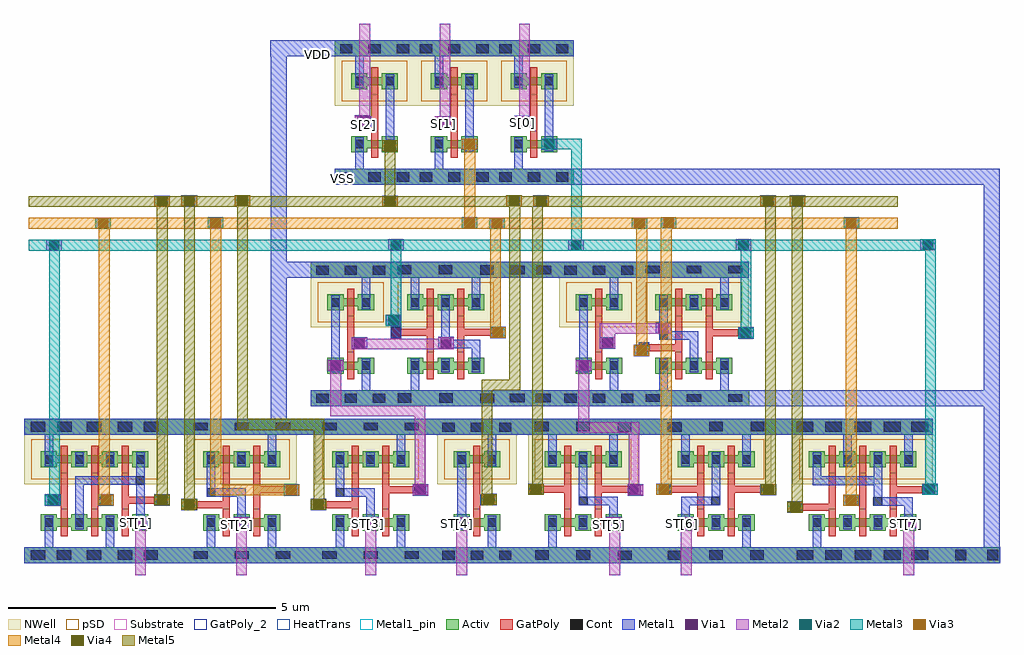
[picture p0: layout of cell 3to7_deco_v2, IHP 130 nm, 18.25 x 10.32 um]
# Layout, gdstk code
from math import pi, radians
import gdstk
lib = gdstk.Library(unit=1e-6, precision=5e-09)
def R(c, l, rs):  # rectangles x0, y0, x1, y1
    for r in rs: c.add(gdstk.rectangle(r[:2], r[2:], *l))
def A(c, l, x, y, w, h, nx, ny, dx, dy):  # array of equal rectangles
    R(c, l, [(x+i*dx, y+j*dy, x+i*dx+w, y+j*dy+h) for i in range(nx) for j in range(ny)])
Activ = (1, 0)
GatPoly = (5, 0)
GatPoly_2 = (5, 2)
Cont = (6, 0)
Metal1 = (8, 0)
Metal1_pin = (8, 2)
Metal2 = (10, 0)
pSD = (14, 0)
Via1 = (19, 0)
Via2 = (29, 0)
Metal3 = (30, 0)
NWell = (31, 0)
Substrate = (40, 0)
Via3 = (49, 0)
Metal4 = (50, 0)
HeatTrans = (51, 0)
Via4 = (66, 0)
Metal5 = (67, 0)

pmos_1 = lib.new_cell('pmos$1')
R(pmos_1, Activ, [(0,0,0.3,0.3), (0.57,0,0.87,0.3), (0,0.075,0.87,0.225)])
R(pmos_1, GatPoly, [(0.37,-0.105,0.5,0.405), (0.37,-0.105,0.5,0.405)])
R(pmos_1, Cont, [(0.07,0.07,0.23,0.23), (0.64,0.07,0.8,0.23)])
R(pmos_1, Metal1, [(0.07,0.02,0.23,0.28), (0.07,0.02,0.23,0.28), (0.64,0.02,0.8,0.28), (0.64,0.02,0.8,0.28)])
R(pmos_1, pSD, [(-0.18,-0.225,1.05,0.525)])
R(pmos_1, NWell, [(-0.31,-0.31,1.18,0.61)])
R(pmos_1, Substrate, [(0.57,0,0.87,0.3)])
R(pmos_1, HeatTrans, [(0.37,-0.105,0.5,0.405)])
pmos_1.add(gdstk.Label('pmos', (0.435,0.15), layer=63, texttype=0))
pmos_1.add(gdstk.Label('pmos', (0.435,0.15), layer=51, texttype=0))

nmos_1 = lib.new_cell('nmos$1')
R(nmos_1, Activ, [(0,0,0.3,0.3), (0.57,0,0.87,0.3), (0,0.075,0.87,0.225)])
R(nmos_1, GatPoly, [(0.37,-0.105,0.5,0.405)])
R(nmos_1, GatPoly_2, [(0.37,-0.105,0.5,0.405)])
R(nmos_1, Cont, [(0.07,0.07,0.23,0.23), (0.64,0.07,0.8,0.23)])
R(nmos_1, Metal1, [(0.07,0.02,0.23,0.28), (0.64,0.02,0.8,0.28)])
R(nmos_1, Metal1_pin, [(0.07,0.02,0.23,0.28), (0.64,0.02,0.8,0.28)])
R(nmos_1, HeatTrans, [(0.37,-0.105,0.5,0.405)])
nmos_1.add(gdstk.Label('nmos', (0.435,0.15), layer=63, texttype=0))
nmos_1.add(gdstk.Label('nmos', (0.435,0.15), layer=51, texttype=0))

pmos_1_1 = lib.new_cell('pmos$1$1')
R(pmos_1_1, Activ, [(0,0,0.3,0.3), (0.57,0,0.87,0.3), (0,0.075,0.87,0.225)])
R(pmos_1_1, GatPoly, [(0.37,-0.105,0.5,0.405), (0.37,-0.105,0.5,0.405)])
R(pmos_1_1, Cont, [(0.07,0.07,0.23,0.23), (0.64,0.07,0.8,0.23)])
R(pmos_1_1, Metal1, [(0.07,0.02,0.23,0.28), (0.07,0.02,0.23,0.28), (0.64,0.02,0.8,0.28), (0.64,0.02,0.8,0.28)])
R(pmos_1_1, pSD, [(-0.18,-0.225,1.05,0.525)])
R(pmos_1_1, NWell, [(-0.31,-0.31,1.18,0.61)])
R(pmos_1_1, Substrate, [(0.57,0,0.87,0.3)])
R(pmos_1_1, HeatTrans, [(0.37,-0.105,0.5,0.405)])
pmos_1_1.add(gdstk.Label('pmos', (0.435,0.15), layer=63, texttype=0))
pmos_1_1.add(gdstk.Label('pmos', (0.435,0.15), layer=51, texttype=0))

nmos_1_1 = lib.new_cell('nmos$1$1')
R(nmos_1_1, Activ, [(0,0,0.3,0.3), (0.57,0,0.87,0.3), (0,0.075,0.87,0.225)])
R(nmos_1_1, GatPoly, [(0.37,-0.105,0.5,0.405)])
R(nmos_1_1, GatPoly_2, [(0.37,-0.105,0.5,0.405)])
R(nmos_1_1, Cont, [(0.07,0.07,0.23,0.23), (0.64,0.07,0.8,0.23)])
R(nmos_1_1, Metal1, [(0.07,0.02,0.23,0.28), (0.64,0.02,0.8,0.28)])
R(nmos_1_1, Metal1_pin, [(0.07,0.02,0.23,0.28), (0.64,0.02,0.8,0.28)])
R(nmos_1_1, HeatTrans, [(0.37,-0.105,0.5,0.405)])
nmos_1_1.add(gdstk.Label('nmos', (0.435,0.15), layer=63, texttype=0))
nmos_1_1.add(gdstk.Label('nmos', (0.435,0.15), layer=51, texttype=0))

pmos_1_2 = lib.new_cell('pmos$1$2')
R(pmos_1_2, Activ, [(0,0,0.3,0.3), (0.57,0,0.87,0.3), (0,0.075,0.87,0.225)])
R(pmos_1_2, GatPoly, [(0.37,-0.105,0.5,0.405), (0.37,-0.105,0.5,0.405)])
R(pmos_1_2, Cont, [(0.07,0.07,0.23,0.23), (0.64,0.07,0.8,0.23)])
R(pmos_1_2, Metal1, [(0.07,0.02,0.23,0.28), (0.07,0.02,0.23,0.28), (0.64,0.02,0.8,0.28), (0.64,0.02,0.8,0.28)])
R(pmos_1_2, pSD, [(-0.18,-0.225,1.05,0.525)])
R(pmos_1_2, NWell, [(-0.31,-0.31,1.18,0.61)])
R(pmos_1_2, Substrate, [(0.57,0,0.87,0.3)])
R(pmos_1_2, HeatTrans, [(0.37,-0.105,0.5,0.405)])
pmos_1_2.add(gdstk.Label('pmos', (0.435,0.15), layer=63, texttype=0))
pmos_1_2.add(gdstk.Label('pmos', (0.435,0.15), layer=51, texttype=0))

nmos_1_2 = lib.new_cell('nmos$1$2')
R(nmos_1_2, Activ, [(0,0,0.3,0.3), (0.57,0,0.87,0.3), (0,0.075,0.87,0.225)])
R(nmos_1_2, GatPoly, [(0.37,-0.105,0.5,0.405)])
R(nmos_1_2, GatPoly_2, [(0.37,-0.105,0.5,0.405)])
R(nmos_1_2, Cont, [(0.07,0.07,0.23,0.23), (0.64,0.07,0.8,0.23)])
R(nmos_1_2, Metal1, [(0.07,0.02,0.23,0.28), (0.64,0.02,0.8,0.28)])
R(nmos_1_2, Metal1_pin, [(0.07,0.02,0.23,0.28), (0.64,0.02,0.8,0.28)])
R(nmos_1_2, HeatTrans, [(0.37,-0.105,0.5,0.405)])
nmos_1_2.add(gdstk.Label('nmos', (0.435,0.15), layer=63, texttype=0))
nmos_1_2.add(gdstk.Label('nmos', (0.435,0.15), layer=51, texttype=0))

inv = lib.new_cell('inv')
R(inv, Activ, [(0.24,0.255,1.73,0.555), (0.24,0.255,1.73,0.555), (0.24,0.255,1.73,0.555), (0.24,0.255,1.73,0.555), (0.24,2.655,1.73,2.955), (0.24,2.655,1.73,2.955), (0.24,2.655,1.73,2.955), (0.24,2.655,1.73,2.955)])
R(inv, GatPoly, [(0.92,0.76,1.05,2.45), (0.92,0.76,1.05,2.45), (0.92,0.76,1.05,2.45), (0.92,0.76,1.05,2.45), (0.72,1.335,0.92,1.535), (0.72,1.335,0.92,1.535), (0.72,1.335,0.92,1.535), (0.72,1.335,0.92,1.535)])
R(inv, Cont, [(0.34,0.315,0.57,0.485), (0.34,0.315,0.57,0.485), (0.34,0.315,0.57,0.485), (0.34,0.315,0.57,0.485), (0.87,0.315,1.1,0.485), (0.87,0.315,1.1,0.485), (0.87,0.315,1.1,0.485), (0.87,0.315,1.1,0.485), (1.4,0.315,1.63,0.485), (1.4,0.315,1.63,0.485), (1.4,0.315,1.63,0.485), (1.4,0.315,1.63,0.485), (0.72,1.335,0.92,1.535), (0.72,1.335,0.92,1.535), (0.72,1.335,0.92,1.535), (0.72,1.335,0.92,1.535), (0.34,2.715,0.57,2.885), (0.34,2.715,0.57,2.885), (0.34,2.715,0.57,2.885), (0.34,2.715,0.57,2.885), (0.87,2.715,1.1,2.885), (0.87,2.715,1.1,2.885), (0.87,2.715,1.1,2.885), (0.87,2.715,1.1,2.885), (1.4,2.715,1.63,2.885), (1.4,2.715,1.63,2.885), (1.4,2.715,1.63,2.885), (1.4,2.715,1.63,2.885)])
R(inv, Metal1, [(0.24,0.255,1.73,0.555), (0.24,0.255,1.73,0.555), (0.24,0.255,1.73,0.555), (0.24,0.255,1.73,0.555), (0.62,0.255,0.78,1.145), (0.62,0.255,0.78,1.145), (0.62,0.255,0.78,1.145), (0.62,0.255,0.78,1.145), (1.19,0.885,1.35,2.325), (1.19,0.885,1.35,2.325), (1.19,0.885,1.35,2.325), (1.19,0.885,1.35,2.325), (0.72,1.335,0.92,1.535), (0.72,1.335,0.92,1.535), (0.72,1.335,0.92,1.535), (0.72,1.335,0.92,1.535), (0.62,2.065,0.78,2.955), (0.62,2.065,0.78,2.955), (0.62,2.065,0.78,2.955), (0.62,2.065,0.78,2.955), (0.24,2.655,1.73,2.955), (0.24,2.655,1.73,2.955), (0.24,2.655,1.73,2.955), (0.24,2.655,1.73,2.955)])
R(inv, Metal1_pin, [(0.24,0.255,1.73,0.555), (0.24,0.255,1.73,0.555), (0.24,0.255,1.73,0.555), (0.24,0.255,1.73,0.555), (1.19,0.885,1.35,2.325), (1.19,0.885,1.35,2.325), (1.19,0.885,1.35,2.325), (1.19,0.885,1.35,2.325), (0.72,1.335,0.92,1.535), (0.72,1.335,0.92,1.535), (0.72,1.335,0.92,1.535), (0.72,1.335,0.92,1.535), (0.24,2.655,1.73,2.955), (0.24,2.655,1.73,2.955), (0.24,2.655,1.73,2.955), (0.24,2.655,1.73,2.955)])
R(inv, pSD, [(0.24,0.255,1.73,0.555), (0.24,0.255,1.73,0.555), (0.24,0.255,1.73,0.555), (0.24,0.255,1.73,0.555)])
R(inv, NWell, [(0.24,2.655,1.73,2.955), (0.24,2.655,1.73,2.955), (0.24,2.655,1.73,2.955), (0.24,2.655,1.73,2.955)])
inv.add(gdstk.Reference(pmos_1, (0.55,2.045)))
inv.add(gdstk.Reference(nmos_1, (0.55,0.865)))
inv.add(gdstk.Reference(pmos_1_1, (0.55,2.045)))
inv.add(gdstk.Reference(nmos_1_1, (0.55,0.865)))
inv.add(gdstk.Reference(pmos_1_2, (0.55,2.045)))
inv.add(gdstk.Reference(nmos_1_2, (0.55,0.865)))
inv.add(gdstk.Label('VIN', (0.78,1.435), layer=8, texttype=25))
inv.add(gdstk.Label('VSS', (0.95,0.37), layer=8, texttype=25))
inv.add(gdstk.Label('VOUT', (1.2,1.665), layer=8, texttype=25))
inv.add(gdstk.Label('VDD', (0.96,2.805), layer=8, texttype=25))
inv.add(gdstk.Label('VIN', (0.78,1.435), layer=8, texttype=25))
inv.add(gdstk.Label('VSS', (0.95,0.37), layer=8, texttype=25))
inv.add(gdstk.Label('VOUT', (1.2,1.665), layer=8, texttype=25))
inv.add(gdstk.Label('VDD', (0.96,2.805), layer=8, texttype=25))
inv.add(gdstk.Label('VIN', (0.78,1.435), layer=8, texttype=25))
inv.add(gdstk.Label('VSS', (0.95,0.37), layer=8, texttype=25))
inv.add(gdstk.Label('VOUT', (1.2,1.665), layer=8, texttype=25))
inv.add(gdstk.Label('VDD', (0.96,2.805), layer=8, texttype=25))
inv.add(gdstk.Label('VIN', (0.78,1.435), layer=8, texttype=25))
inv.add(gdstk.Label('VSS', (0.95,0.37), layer=8, texttype=25))
inv.add(gdstk.Label('VOUT', (1.2,1.665), layer=8, texttype=25))
inv.add(gdstk.Label('VDD', (0.96,2.805), layer=8, texttype=25))

nmos_3 = lib.new_cell('nmos$3')
R(nmos_3, Activ, [(0,0,0.3,0.3), (0.57,0,0.87,0.3), (0,0.075,0.87,0.225)])
R(nmos_3, GatPoly, [(0.37,-0.105,0.5,0.405)])
R(nmos_3, GatPoly_2, [(0.37,-0.105,0.5,0.405)])
R(nmos_3, Cont, [(0.07,0.07,0.23,0.23), (0.64,0.07,0.8,0.23)])
R(nmos_3, Metal1, [(0.07,0.02,0.23,0.28), (0.64,0.02,0.8,0.28)])
R(nmos_3, Metal1_pin, [(0.07,0.02,0.23,0.28), (0.64,0.02,0.8,0.28)])
R(nmos_3, HeatTrans, [(0.37,-0.105,0.5,0.405)])
nmos_3.add(gdstk.Label('nmos', (0.435,0.15), layer=63, texttype=0))
nmos_3.add(gdstk.Label('nmos', (0.435,0.15), layer=51, texttype=0))

pmos_3 = lib.new_cell('pmos$3')
R(pmos_3, Activ, [(0,0,0.3,0.3), (0.57,0,0.87,0.3), (0,0.075,0.87,0.225)])
R(pmos_3, GatPoly, [(0.37,-0.105,0.5,0.405), (0.37,-0.105,0.5,0.405)])
R(pmos_3, Cont, [(0.07,0.07,0.23,0.23), (0.64,0.07,0.8,0.23)])
R(pmos_3, Metal1, [(0.07,0.02,0.23,0.28), (0.07,0.02,0.23,0.28), (0.64,0.02,0.8,0.28), (0.64,0.02,0.8,0.28)])
R(pmos_3, pSD, [(-0.18,-0.225,1.05,0.525)])
R(pmos_3, NWell, [(-0.31,-0.31,1.18,0.61)])
R(pmos_3, Substrate, [(0.57,0,0.87,0.3)])
R(pmos_3, HeatTrans, [(0.37,-0.105,0.5,0.405)])
pmos_3.add(gdstk.Label('pmos', (0.435,0.15), layer=63, texttype=0))
pmos_3.add(gdstk.Label('pmos', (0.435,0.15), layer=51, texttype=0))

nmos_2_1 = lib.new_cell('nmos$2$1')
R(nmos_2_1, Activ, [(0,0,0.3,0.3), (0.57,0,0.87,0.3), (0,0.075,0.87,0.225)])
R(nmos_2_1, GatPoly, [(0.37,-0.105,0.5,0.405)])
R(nmos_2_1, GatPoly_2, [(0.37,-0.105,0.5,0.405)])
R(nmos_2_1, Cont, [(0.07,0.07,0.23,0.23), (0.64,0.07,0.8,0.23)])
R(nmos_2_1, Metal1, [(0.07,0.02,0.23,0.28), (0.64,0.02,0.8,0.28)])
R(nmos_2_1, Metal1_pin, [(0.07,0.02,0.23,0.28), (0.64,0.02,0.8,0.28)])
R(nmos_2_1, HeatTrans, [(0.37,-0.105,0.5,0.405)])
nmos_2_1.add(gdstk.Label('nmos', (0.435,0.15), layer=63, texttype=0))
nmos_2_1.add(gdstk.Label('nmos', (0.435,0.15), layer=51, texttype=0))

pmos_2_1 = lib.new_cell('pmos$2$1')
R(pmos_2_1, Activ, [(0,0,0.3,0.3), (0.57,0,0.87,0.3), (0,0.075,0.87,0.225)])
R(pmos_2_1, GatPoly, [(0.37,-0.105,0.5,0.405), (0.37,-0.105,0.5,0.405)])
R(pmos_2_1, Cont, [(0.07,0.07,0.23,0.23), (0.64,0.07,0.8,0.23)])
R(pmos_2_1, Metal1, [(0.07,0.02,0.23,0.28), (0.07,0.02,0.23,0.28), (0.64,0.02,0.8,0.28), (0.64,0.02,0.8,0.28)])
R(pmos_2_1, pSD, [(-0.18,-0.225,1.05,0.525)])
R(pmos_2_1, NWell, [(-0.31,-0.31,1.18,0.61)])
R(pmos_2_1, Substrate, [(0.57,0,0.87,0.3)])
R(pmos_2_1, HeatTrans, [(0.37,-0.105,0.5,0.405)])
pmos_2_1.add(gdstk.Label('pmos', (0.435,0.15), layer=63, texttype=0))
pmos_2_1.add(gdstk.Label('pmos', (0.435,0.15), layer=51, texttype=0))

nand_custom = lib.new_cell('nand_custom')
R(nand_custom, Activ, [(0.95,1.7,3.01,2), (0.95,1.7,3.01,2), (0.95,1.7,3.01,2), (0.95,4.1,3.01,4.4), (0.95,4.1,3.01,4.4), (0.95,4.1,3.01,4.4)])
R(nand_custom, GatPoly, [(1.63,2.205,1.76,3.895), (1.63,2.205,1.76,3.895), (1.63,2.205,1.76,3.895), (2.2,2.205,2.33,3.895), (2.2,2.205,2.33,3.895), (2.2,2.205,2.33,3.895), (0.95,2.975,1.15,3.175), (0.95,2.975,1.15,3.175), (0.95,2.975,1.15,3.175), (2.81,2.975,3.01,3.175), (2.81,2.975,3.01,3.175), (2.81,2.975,3.01,3.175), (1.15,3.02,1.76,3.15), (1.15,3.02,1.76,3.15), (1.15,3.02,1.76,3.15), (2.2,3.02,2.81,3.15), (2.2,3.02,2.81,3.15), (2.2,3.02,2.81,3.15)])
R(nand_custom, Cont, [(1.075,1.76,1.33,1.935), (1.075,1.76,1.33,1.935), (1.075,1.76,1.33,1.935), (1.85,1.765,2.105,1.94), (1.85,1.765,2.105,1.94), (1.85,1.765,2.105,1.94), (2.62,1.765,2.875,1.94), (2.62,1.765,2.875,1.94), (2.62,1.765,2.875,1.94), (1.895,2.785,2.06,2.945), (1.895,2.785,2.06,2.945), (1.895,2.785,2.06,2.945), (0.95,2.975,1.15,3.175), (0.95,2.975,1.15,3.175), (0.95,2.975,1.15,3.175), (2.81,2.975,3.01,3.175), (2.81,2.975,3.01,3.175), (2.81,2.975,3.01,3.175), (1.08,4.16,1.335,4.335), (1.08,4.16,1.335,4.335), (1.08,4.16,1.335,4.335), (1.855,4.165,2.11,4.34), (1.855,4.165,2.11,4.34), (1.855,4.165,2.11,4.34), (2.625,4.165,2.88,4.34), (2.625,4.165,2.88,4.34), (2.625,4.165,2.88,4.34)])
R(nand_custom, Metal1, [(0.95,1.7,3.01,2), (0.95,1.7,3.01,2), (0.95,1.7,3.01,2), (2.47,1.7,2.63,2.59), (2.47,1.7,2.63,2.59), (2.47,1.7,2.63,2.59), (1.33,2.33,1.49,2.945), (1.33,2.33,1.49,2.945), (1.33,2.33,1.49,2.945), (1.33,2.785,2.06,2.945), (1.33,2.785,2.06,2.945), (1.33,2.785,2.06,2.945), (1.9,2.785,2.06,3.77), (1.9,2.785,2.06,3.77), (1.9,2.785,2.06,3.77), (0.95,2.975,1.15,3.175), (0.95,2.975,1.15,3.175), (0.95,2.975,1.15,3.175), (2.81,2.975,3.01,3.175), (2.81,2.975,3.01,3.175), (2.81,2.975,3.01,3.175), (1.33,3.51,1.49,4.4), (1.33,3.51,1.49,4.4), (1.33,3.51,1.49,4.4), (2.47,3.51,2.63,4.4), (2.47,3.51,2.63,4.4), (2.47,3.51,2.63,4.4), (0.95,4.1,3.01,4.4), (0.95,4.1,3.01,4.4), (0.95,4.1,3.01,4.4)])
R(nand_custom, Metal1_pin, [(0.95,1.7,3.01,2), (0.95,1.7,3.01,2), (0.95,1.7,3.01,2), (1.9,2.785,2.06,3.77), (1.9,2.785,2.06,3.77), (1.9,2.785,2.06,3.77), (0.95,2.975,1.15,3.175), (0.95,2.975,1.15,3.175), (0.95,2.975,1.15,3.175), (2.81,2.975,3.01,3.175), (2.81,2.975,3.01,3.175), (2.81,2.975,3.01,3.175), (0.95,4.1,3.01,4.4), (0.95,4.1,3.01,4.4), (0.95,4.1,3.01,4.4)])
R(nand_custom, pSD, [(0.95,1.7,3.01,2), (0.95,1.7,3.01,2), (0.95,1.7,3.01,2)])
R(nand_custom, NWell, [(0.95,4.1,3.01,4.4), (0.95,4.1,3.01,4.4), (0.95,4.1,3.01,4.4)])
nand_custom.add(gdstk.Reference(nmos_3, (1.26,2.31)))
nand_custom.add(gdstk.Reference(nmos_3, (1.83,2.31)))
nand_custom.add(gdstk.Reference(pmos_3, (2.7,3.79), rotation=pi))
nand_custom.add(gdstk.Reference(pmos_3, (1.26,3.49)))
nand_custom.add(gdstk.Reference(nmos_2_1, (1.26,2.31)))
nand_custom.add(gdstk.Reference(nmos_2_1, (1.83,2.31)))
nand_custom.add(gdstk.Reference(pmos_2_1, (2.7,3.79), rotation=pi))
nand_custom.add(gdstk.Reference(pmos_2_1, (1.26,3.49)))
nand_custom.add(gdstk.Label('VSS', (1.94,1.84), layer=8, texttype=25))
nand_custom.add(gdstk.Label('A', (1.05,3.075), layer=8, texttype=25))
nand_custom.add(gdstk.Label('OUT', (1.925,2.83), layer=8, texttype=25))
nand_custom.add(gdstk.Label('B', (2.89,3.08), layer=8, texttype=25))
nand_custom.add(gdstk.Label('VDD', (1.93,4.21), layer=8, texttype=25))
nand_custom.add(gdstk.Label('VSS', (1.94,1.84), layer=8, texttype=25))
nand_custom.add(gdstk.Label('A', (1.05,3.075), layer=8, texttype=25))
nand_custom.add(gdstk.Label('OUT', (1.925,2.83), layer=8, texttype=25))
nand_custom.add(gdstk.Label('B', (2.89,3.08), layer=8, texttype=25))
nand_custom.add(gdstk.Label('VDD', (1.93,4.21), layer=8, texttype=25))
nand_custom.add(gdstk.Label('VSS', (1.94,1.84), layer=8, texttype=25))
nand_custom.add(gdstk.Label('A', (1.05,3.075), layer=8, texttype=25))
nand_custom.add(gdstk.Label('OUT', (1.925,2.83), layer=8, texttype=25))
nand_custom.add(gdstk.Label('B', (2.89,3.08), layer=8, texttype=25))
nand_custom.add(gdstk.Label('VDD', (1.93,4.21), layer=8, texttype=25))

via_stack_1 = lib.new_cell('via_stack$1')
R(via_stack_1, Metal1, [(-0.145,-0.105,0.145,0.105)])
R(via_stack_1, Metal2, [(-0.145,-0.1,0.145,0.1)])
R(via_stack_1, Via1, [(-0.095,-0.095,0.095,0.095)])

and_custom = lib.new_cell('and_custom')
R(and_custom, Metal2, [(2.61,1.32,4.515,1.52)])
and_custom.add(gdstk.Reference(inv, (3.55,0)))
and_custom.add(gdstk.Reference(nand_custom, (0.78,-1.445)))
and_custom.add(gdstk.Reference(via_stack_1, (4.37,1.435)))
and_custom.add(gdstk.Reference(via_stack_1, (2.755,1.445)))
and_custom.add(gdstk.Label('A', (1.775,1.61), layer=8, texttype=25))
and_custom.add(gdstk.Label('B', (3.69,1.63), layer=8, texttype=25))
and_custom.add(gdstk.Label('VSS', (1.925,0.385), layer=8, texttype=25))
and_custom.add(gdstk.Label('VDD', (1.93,2.765), layer=8, texttype=25))
and_custom.add(gdstk.Label('OUT', (4.775,1.6), layer=8, texttype=25))

via_stack = lib.new_cell('via_stack')
R(via_stack, Metal1, [(-0.145,-0.105,0.145,0.105)])
R(via_stack, Metal2, [(-0.145,-0.1,0.145,0.1)])
R(via_stack, Via1, [(-0.095,-0.095,0.095,0.095)])

pmos_2 = lib.new_cell('pmos$2')
R(pmos_2, Activ, [(0,0,0.3,0.3), (0.57,0,0.87,0.3), (0,0.075,0.87,0.225)])
R(pmos_2, GatPoly, [(0.37,-0.105,0.5,0.405), (0.37,-0.105,0.5,0.405)])
R(pmos_2, Cont, [(0.07,0.07,0.23,0.23), (0.64,0.07,0.8,0.23)])
R(pmos_2, Metal1, [(0.07,0.02,0.23,0.28), (0.07,0.02,0.23,0.28), (0.64,0.02,0.8,0.28), (0.64,0.02,0.8,0.28)])
R(pmos_2, pSD, [(-0.18,-0.225,1.05,0.525)])
R(pmos_2, NWell, [(-0.31,-0.31,1.18,0.61)])
R(pmos_2, Substrate, [(0.57,0,0.87,0.3)])
R(pmos_2, HeatTrans, [(0.37,-0.105,0.5,0.405)])
pmos_2.add(gdstk.Label('pmos', (0.435,0.15), layer=63, texttype=0))
pmos_2.add(gdstk.Label('pmos', (0.435,0.15), layer=51, texttype=0))

nmos_2 = lib.new_cell('nmos$2')
R(nmos_2, Activ, [(0,0,0.3,0.3), (0.57,0,0.87,0.3), (0,0.075,0.87,0.225)])
R(nmos_2, GatPoly, [(0.37,-0.105,0.5,0.405)])
R(nmos_2, GatPoly_2, [(0.37,-0.105,0.5,0.405)])
R(nmos_2, Cont, [(0.07,0.07,0.23,0.23), (0.64,0.07,0.8,0.23)])
R(nmos_2, Metal1, [(0.07,0.02,0.23,0.28), (0.64,0.02,0.8,0.28)])
R(nmos_2, Metal1_pin, [(0.07,0.02,0.23,0.28), (0.64,0.02,0.8,0.28)])
R(nmos_2, HeatTrans, [(0.37,-0.105,0.5,0.405)])
nmos_2.add(gdstk.Label('nmos', (0.435,0.15), layer=63, texttype=0))
nmos_2.add(gdstk.Label('nmos', (0.435,0.15), layer=51, texttype=0))

pmos_4 = lib.new_cell('pmos$4')
R(pmos_4, Activ, [(0,0,0.3,0.3), (0.57,0,0.87,0.3), (0,0.075,0.87,0.225)])
R(pmos_4, GatPoly, [(0.37,-0.105,0.5,0.405), (0.37,-0.105,0.5,0.405)])
R(pmos_4, Cont, [(0.07,0.07,0.23,0.23), (0.64,0.07,0.8,0.23)])
R(pmos_4, Metal1, [(0.07,0.02,0.23,0.28), (0.07,0.02,0.23,0.28), (0.64,0.02,0.8,0.28), (0.64,0.02,0.8,0.28)])
R(pmos_4, pSD, [(-0.18,-0.225,1.05,0.525)])
R(pmos_4, NWell, [(-0.31,-0.31,1.18,0.61)])
R(pmos_4, Substrate, [(0.57,0,0.87,0.3)])
R(pmos_4, HeatTrans, [(0.37,-0.105,0.5,0.405)])
pmos_4.add(gdstk.Label('pmos', (0.435,0.15), layer=63, texttype=0))
pmos_4.add(gdstk.Label('pmos', (0.435,0.15), layer=51, texttype=0))

nmos_4 = lib.new_cell('nmos$4')
R(nmos_4, Activ, [(0,0,0.3,0.3), (0.57,0,0.87,0.3), (0,0.075,0.87,0.225)])
R(nmos_4, GatPoly, [(0.37,-0.105,0.5,0.405)])
R(nmos_4, GatPoly_2, [(0.37,-0.105,0.5,0.405)])
R(nmos_4, Cont, [(0.07,0.07,0.23,0.23), (0.64,0.07,0.8,0.23)])
R(nmos_4, Metal1, [(0.07,0.02,0.23,0.28), (0.64,0.02,0.8,0.28)])
R(nmos_4, Metal1_pin, [(0.07,0.02,0.23,0.28), (0.64,0.02,0.8,0.28)])
R(nmos_4, HeatTrans, [(0.37,-0.105,0.5,0.405)])
nmos_4.add(gdstk.Label('nmos', (0.435,0.15), layer=63, texttype=0))
nmos_4.add(gdstk.Label('nmos', (0.435,0.15), layer=51, texttype=0))

nor_custom = lib.new_cell('nor_custom')
R(nor_custom, Activ, [(0.165,0.28,2.225,0.58), (0.165,0.28,2.225,0.58), (0.17,2.68,2.23,2.98), (0.17,2.68,2.23,2.98)])
R(nor_custom, GatPoly, [(0.85,0.785,0.98,2.475), (0.85,0.785,0.98,2.475), (1.42,0.785,1.55,2.475), (1.42,0.785,1.55,2.475), (1.42,1.31,2.03,1.44), (1.42,1.31,2.03,1.44), (0.37,1.585,0.98,1.715), (0.37,1.585,0.98,1.715)])
R(nor_custom, Cont, [(0.295,0.36,0.56,0.505), (0.295,0.36,0.56,0.505), (1.065,0.36,1.33,0.505), (1.065,0.36,1.33,0.505), (1.835,0.36,2.1,0.505), (1.835,0.36,2.1,0.505), (2.03,1.275,2.23,1.475), (2.03,1.275,2.23,1.475), (1.69,1.52,1.85,1.68), (1.69,1.52,1.85,1.68), (0.17,1.55,0.37,1.75), (0.17,1.55,0.37,1.75), (0.295,2.765,0.56,2.91), (0.295,2.765,0.56,2.91), (1.065,2.765,1.33,2.91), (1.065,2.765,1.33,2.91), (1.835,2.765,2.1,2.91), (1.835,2.765,2.1,2.91)])
R(nor_custom, Metal1, [(0.165,0.28,2.225,0.58), (0.165,0.28,2.225,0.58), (0.55,0.28,0.71,1.17), (0.55,0.28,0.71,1.17), (1.69,0.28,1.85,1.17), (1.69,0.28,1.85,1.17), (1.12,0.91,1.28,1.68), (1.12,0.91,1.28,1.68), (2.03,1.275,2.23,1.475), (2.03,1.275,2.23,1.475), (1.12,1.52,1.85,1.68), (1.12,1.52,1.85,1.68), (1.69,1.52,1.85,2.35), (1.69,1.52,1.85,2.35), (0.17,1.55,0.37,1.75), (0.17,1.55,0.37,1.75), (0.55,2.09,0.71,2.98), (0.55,2.09,0.71,2.98), (0.17,2.68,2.23,2.98), (0.17,2.68,2.23,2.98)])
R(nor_custom, Metal1_pin, [(0.165,0.28,2.225,0.58), (0.165,0.28,2.225,0.58), (2.03,1.275,2.23,1.475), (2.03,1.275,2.23,1.475), (1.69,1.52,1.85,2.35), (1.69,1.52,1.85,2.35), (0.17,1.55,0.37,1.75), (0.17,1.55,0.37,1.75), (0.17,2.68,2.23,2.98), (0.17,2.68,2.23,2.98)])
R(nor_custom, pSD, [(0.165,0.28,2.225,0.58), (0.165,0.28,2.225,0.58)])
R(nor_custom, NWell, [(0.17,2.68,2.23,2.98), (0.17,2.68,2.23,2.98)])
nor_custom.add(gdstk.Reference(pmos_2, (0.48,2.07)))
nor_custom.add(gdstk.Reference(pmos_2, (1.05,2.07)))
nor_custom.add(gdstk.Reference(nmos_2, (1.92,1.19), rotation=pi))
nor_custom.add(gdstk.Reference(nmos_2, (0.48,0.89)))
nor_custom.add(gdstk.Reference(pmos_4, (0.48,2.07)))
nor_custom.add(gdstk.Reference(pmos_4, (1.05,2.07)))
nor_custom.add(gdstk.Reference(nmos_4, (1.92,1.19), rotation=pi))
nor_custom.add(gdstk.Reference(nmos_4, (0.48,0.89)))
nor_custom.add(gdstk.Label('VSS', (1.155,0.405), layer=8, texttype=25))
nor_custom.add(gdstk.Label('A', (0.23,1.6), layer=8, texttype=25))
nor_custom.add(gdstk.Label('B', (2.085,1.35), layer=8, texttype=25))
nor_custom.add(gdstk.Label('OUT', (1.735,1.555), layer=8, texttype=25))
nor_custom.add(gdstk.Label('VDD', (1.13,2.815), layer=8, texttype=25))
nor_custom.add(gdstk.Label('VSS', (1.155,0.405), layer=8, texttype=25))
nor_custom.add(gdstk.Label('A', (0.23,1.6), layer=8, texttype=25))
nor_custom.add(gdstk.Label('B', (2.085,1.35), layer=8, texttype=25))
nor_custom.add(gdstk.Label('OUT', (1.735,1.555), layer=8, texttype=25))
nor_custom.add(gdstk.Label('VDD', (1.13,2.815), layer=8, texttype=25))

or_custom = lib.new_cell('or_custom')
R(or_custom, Activ, [(0.165,0.28,3.72,0.58)])
R(or_custom, Metal1, [(0.165,0.28,3.72,0.58), (0.165,0.28,3.72,0.58)])
R(or_custom, Metal1_pin, [(0.165,0.28,3.72,0.58)])
R(or_custom, Metal2, [(2.665,1.36,2.955,1.835), (1.625,1.635,2.955,1.835)])
or_custom.add(gdstk.Reference(inv, (1.99,0.025)))
or_custom.add(gdstk.Reference(via_stack, (2.81,1.46)))
or_custom.add(gdstk.Reference(via_stack, (1.77,1.735)))
or_custom.add(gdstk.Reference(nor_custom, (0,0)))
or_custom.add(gdstk.Label('OUT', (3.23,1.65), layer=8, texttype=25))
or_custom.add(gdstk.Label('A', (0.27,1.65), layer=8, texttype=25))
or_custom.add(gdstk.Label('B', (2.105,1.335), layer=8, texttype=25))
or_custom.add(gdstk.Label('VSS', (1.915,0.395), layer=8, texttype=25))
or_custom.add(gdstk.Label('VDD', (1.885,2.82), layer=8, texttype=25))

via_stack_3 = lib.new_cell('via_stack$3')
R(via_stack_3, Metal1, [(-0.145,-0.105,0.145,0.105)])
R(via_stack_3, Metal2, [(-0.145,-0.1,0.145,0.1)])
R(via_stack_3, Via1, [(-0.095,-0.095,0.095,0.095)])
R(via_stack_3, Via2, [(-0.095,-0.095,0.095,0.095)])
R(via_stack_3, Metal3, [(-0.145,-0.1,0.145,0.1)])
R(via_stack_3, Via3, [(-0.095,-0.095,0.095,0.095)])
R(via_stack_3, Metal4, [(-0.145,-0.1,0.145,0.1)])
R(via_stack_3, Via4, [(-0.095,-0.095,0.095,0.095)])
R(via_stack_3, Metal5, [(-0.145,-0.1,0.145,0.1)])

via_stack_4 = lib.new_cell('via_stack$4')
R(via_stack_4, Metal1, [(-0.145,-0.105,0.145,0.105)])
R(via_stack_4, Metal2, [(-0.145,-0.1,0.145,0.1)])
R(via_stack_4, Via1, [(-0.095,-0.095,0.095,0.095)])
R(via_stack_4, Via2, [(-0.095,-0.095,0.095,0.095)])
R(via_stack_4, Metal3, [(-0.145,-0.1,0.145,0.1)])
R(via_stack_4, Via3, [(-0.095,-0.095,0.095,0.095)])
R(via_stack_4, Metal4, [(-0.145,-0.1,0.145,0.1)])

via_stack_6 = lib.new_cell('via_stack$6')
R(via_stack_6, Metal1, [(-0.145,-0.105,0.145,0.105)])
R(via_stack_6, Metal2, [(-0.145,-0.1,0.145,0.1)])
R(via_stack_6, Via1, [(-0.095,-0.095,0.095,0.095)])
R(via_stack_6, Via2, [(-0.095,-0.095,0.095,0.095)])
R(via_stack_6, Metal3, [(-0.145,-0.1,0.145,0.1)])

pmos_5 = lib.new_cell('pmos$5')
R(pmos_5, Activ, [(0,0,0.3,0.3), (0.57,0,0.87,0.3), (0,0.075,0.87,0.225)])
R(pmos_5, GatPoly, [(0.37,-0.105,0.5,0.405), (0.37,-0.105,0.5,0.405)])
R(pmos_5, Cont, [(0.07,0.07,0.23,0.23), (0.64,0.07,0.8,0.23)])
R(pmos_5, Metal1, [(0.07,0.02,0.23,0.28), (0.07,0.02,0.23,0.28), (0.64,0.02,0.8,0.28), (0.64,0.02,0.8,0.28)])
R(pmos_5, pSD, [(-0.18,-0.225,1.05,0.525)])
R(pmos_5, NWell, [(-0.31,-0.31,1.18,0.61)])
R(pmos_5, Substrate, [(0.57,0,0.87,0.3)])
R(pmos_5, HeatTrans, [(0.37,-0.105,0.5,0.405)])
pmos_5.add(gdstk.Label('pmos', (0.435,0.15), layer=63, texttype=0))
pmos_5.add(gdstk.Label('pmos', (0.435,0.15), layer=51, texttype=0))

nmos_5 = lib.new_cell('nmos$5')
R(nmos_5, Activ, [(0,0,0.3,0.3), (0.57,0,0.87,0.3), (0,0.075,0.87,0.225)])
R(nmos_5, GatPoly, [(0.37,-0.105,0.5,0.405)])
R(nmos_5, GatPoly_2, [(0.37,-0.105,0.5,0.405)])
R(nmos_5, Cont, [(0.07,0.07,0.23,0.23), (0.64,0.07,0.8,0.23)])
R(nmos_5, Metal1, [(0.07,0.02,0.23,0.28), (0.64,0.02,0.8,0.28)])
R(nmos_5, Metal1_pin, [(0.07,0.02,0.23,0.28), (0.64,0.02,0.8,0.28)])
R(nmos_5, HeatTrans, [(0.37,-0.105,0.5,0.405)])
nmos_5.add(gdstk.Label('nmos', (0.435,0.15), layer=63, texttype=0))
nmos_5.add(gdstk.Label('nmos', (0.435,0.15), layer=51, texttype=0))

nand_x3_custom = lib.new_cell('nand_x3_custom')
R(nand_x3_custom, Activ, [(0.82,3.075,3.45,3.375), (0.82,5.475,3.45,5.775)])
A(nand_x3_custom, GatPoly, 1.5, 3.58, 0.13, 1.69, 3, 1, 0.57, 0)
R(nand_x3_custom, GatPoly, [(2.64,4.055,3.25,4.185), (1.02,4.385,1.5,4.515)])
A(nand_x3_custom, Cont, 1.425, 3.135, 0.31, 0.185, 3, 2, 0.55, 2.395)
R(nand_x3_custom, Cont, [(0.91,3.135,1.22,3.32), (3.055,3.135,3.365,3.32), (3.25,4.02,3.45,4.22), (2.2,4.145,2.4,4.345), (1.77,4.15,1.935,4.31), (0.82,4.35,1.02,4.55), (0.91,5.53,1.22,5.715), (3.055,5.53,3.365,5.715)])
R(nand_x3_custom, Metal1, [(0.82,3.075,3.45,3.375), (2.91,3.075,3.07,3.965), (1.2,3.705,1.36,4.305), (3.25,4.02,3.45,4.22), (1.2,4.145,1.93,4.305), (1.77,4.145,1.93,5.145), (2.2,4.145,2.4,4.345), (0.82,4.35,1.02,4.55), (1.77,4.535,3.07,4.7), (2.91,4.535,3.07,5.145), (1.2,4.885,1.36,5.775), (2.34,4.885,2.5,5.775), (0.82,5.475,3.45,5.775)])
R(nand_x3_custom, Metal1_pin, [(0.82,3.075,3.45,3.375), (3.25,4.02,3.45,4.22), (1.77,4.145,1.93,5.145), (2.2,4.145,2.4,4.345), (0.82,4.35,1.02,4.55), (0.82,5.475,3.45,5.775)])
R(nand_x3_custom, pSD, [(0.82,3.075,3.45,3.375)])
R(nand_x3_custom, NWell, [(0.82,5.475,3.45,5.775)])
nand_x3_custom.add(gdstk.Reference(pmos_5, (2.57,5.165), rotation=pi))
nand_x3_custom.add(gdstk.Reference(pmos_5, (2.27,4.865)))
nand_x3_custom.add(gdstk.Reference(nmos_5, (2,3.985), rotation=pi))
nand_x3_custom.add(gdstk.Reference(nmos_5, (2.57,3.985), rotation=pi))
nand_x3_custom.add(gdstk.Reference(nmos_5, (3.14,3.985), rotation=pi))
nand_x3_custom.add(gdstk.Reference(pmos_5, (1.13,4.865)))
nand_x3_custom.add(gdstk.Label('C', (3.355,4.08), layer=8, texttype=25))
nand_x3_custom.add(gdstk.Label('VSS', (2.135,3.185), layer=8, texttype=25))
nand_x3_custom.add(gdstk.Label('A', (0.88,4.4), layer=8, texttype=25))
nand_x3_custom.add(gdstk.Label('B', (2.28,4.2), layer=8, texttype=25))
nand_x3_custom.add(gdstk.Label('OUT', (1.785,4.205), layer=8, texttype=25))
nand_x3_custom.add(gdstk.Label('VDD', (2.075,5.575), layer=8, texttype=25))

nmos = lib.new_cell('nmos')
R(nmos, Activ, [(0,0,0.3,0.3), (0.57,0,0.87,0.3), (0,0.075,0.87,0.225)])
R(nmos, GatPoly, [(0.37,-0.105,0.5,0.405)])
R(nmos, GatPoly_2, [(0.37,-0.105,0.5,0.405)])
R(nmos, Cont, [(0.07,0.07,0.23,0.23), (0.64,0.07,0.8,0.23)])
R(nmos, Metal1, [(0.07,0.02,0.23,0.28), (0.64,0.02,0.8,0.28)])
R(nmos, Metal1_pin, [(0.07,0.02,0.23,0.28), (0.64,0.02,0.8,0.28)])
R(nmos, HeatTrans, [(0.37,-0.105,0.5,0.405)])
nmos.add(gdstk.Label('nmos', (0.435,0.15), layer=63, texttype=0))
nmos.add(gdstk.Label('nmos', (0.435,0.15), layer=51, texttype=0))

pmos = lib.new_cell('pmos')
R(pmos, Activ, [(0,0,0.3,0.3), (0.57,0,0.87,0.3), (0,0.075,0.87,0.225)])
R(pmos, GatPoly, [(0.37,-0.105,0.5,0.405), (0.37,-0.105,0.5,0.405)])
R(pmos, Cont, [(0.07,0.07,0.23,0.23), (0.64,0.07,0.8,0.23)])
R(pmos, Metal1, [(0.07,0.02,0.23,0.28), (0.07,0.02,0.23,0.28), (0.64,0.02,0.8,0.28), (0.64,0.02,0.8,0.28)])
R(pmos, pSD, [(-0.18,-0.225,1.05,0.525)])
R(pmos, NWell, [(-0.31,-0.31,1.18,0.61)])
R(pmos, Substrate, [(0.57,0,0.87,0.3)])
R(pmos, HeatTrans, [(0.37,-0.105,0.5,0.405)])
pmos.add(gdstk.Label('pmos', (0.435,0.15), layer=63, texttype=0))
pmos.add(gdstk.Label('pmos', (0.435,0.15), layer=51, texttype=0))

nor_x3_custom = lib.new_cell('nor_x3_custom')
R(nor_x3_custom, Activ, [(0.985,0.865,3.61,1.165), (0.99,3.265,3.62,3.565)])
A(nor_x3_custom, GatPoly, 1.67, 1.37, 0.13, 1.69, 3, 1, 0.57, 0)
R(nor_x3_custom, GatPoly, [(2.81,1.98,3.42,2.11)])
R(nor_x3_custom, Cont, [(1.11,0.925,1.38,1.105), (1.6,0.925,1.87,1.105), (2.155,0.925,2.425,1.105), (2.735,0.925,3.005,1.105), (3.22,0.925,3.49,1.105), (1.47,1.945,1.67,2.145), (2.37,1.945,2.57,2.145), (3.42,1.945,3.62,2.145), (3.075,2.33,3.24,2.49), (1.115,3.325,1.385,3.505), (1.605,3.325,1.875,3.505), (2.16,3.325,2.43,3.505), (2.74,3.325,3.01,3.505), (3.225,3.325,3.495,3.505)])
R(nor_x3_custom, Metal1, [(0.985,0.865,3.61,1.165), (1.37,0.865,1.53,1.755), (2.51,0.865,2.67,1.755), (1.94,1.495,2.1,2.49), (3.08,1.495,3.24,2.935), (1.47,1.945,1.67,2.145), (2.37,1.945,2.57,2.145), (3.42,1.945,3.62,2.145), (1.94,2.33,3.24,2.49), (1.37,2.675,1.53,3.565), (0.99,3.265,3.62,3.565)])
R(nor_x3_custom, Metal1_pin, [(0.985,0.865,3.61,1.165), (3.08,1.495,3.24,2.935), (1.47,1.945,1.67,2.145), (2.37,1.945,2.57,2.145), (3.42,1.945,3.62,2.145), (0.99,3.265,3.62,3.565)])
R(nor_x3_custom, pSD, [(0.985,0.865,3.61,1.165)])
R(nor_x3_custom, NWell, [(0.99,3.265,3.62,3.565)])
nor_x3_custom.add(gdstk.Reference(nmos, (1.3,1.475)))
nor_x3_custom.add(gdstk.Reference(pmos, (1.3,2.655)))
nor_x3_custom.add(gdstk.Reference(pmos, (1.87,2.655)))
nor_x3_custom.add(gdstk.Reference(pmos, (2.44,2.655)))
nor_x3_custom.add(gdstk.Reference(nmos, (2.44,1.475)))
nor_x3_custom.add(gdstk.Reference(nmos, (2.74,1.775), rotation=pi))
nor_x3_custom.add(gdstk.Label('VSS', (2.235,0.985), layer=8, texttype=25))
nor_x3_custom.add(gdstk.Label('OUT', (3.095,2.355), layer=8, texttype=25))
nor_x3_custom.add(gdstk.Label('B', (2.465,2.01), layer=8, texttype=25))
nor_x3_custom.add(gdstk.Label('C', (3.515,2.01), layer=8, texttype=25))
nor_x3_custom.add(gdstk.Label('A', (1.55,2.015), layer=8, texttype=25))
nor_x3_custom.add(gdstk.Label('VDD', (2.225,3.37), layer=8, texttype=25))

c_3to7_deco_v2 = lib.new_cell('3to7_deco_v2')
R(c_3to7_deco_v2, Activ, [(0.035,0.805,17.03,1.105), (17.03,0.805,18.28,1.105), (0.04,3.205,17.03,3.505), (8.95,3.74,10.04,4.04), (8.95,6.14,10.045,6.44)])
R(c_3to7_deco_v2, Cont, [(17.45,0.855,17.65,1.055), (18.05,0.855,18.25,1.055), (9.12,3.81,9.4,3.97), (9.605,3.81,9.885,3.97), (6.89,5.015,7.09,5.44), (9.12,6.205,9.4,6.365), (9.615,6.205,9.895,6.365)])
R(c_3to7_deco_v2, Metal1, [(0.035,0.805,17.03,1.105), (17.03,0.805,18.285,1.105), (17.98,0.805,18.28,8.18), (0.04,3.205,17.03,3.505), (4.645,3.205,4.945,6.455), (8.95,3.74,10.04,4.04), (13.595,3.74,18.28,4.04), (6.89,5.015,7.09,5.435), (4.645,6.14,5.4,6.44), (4.645,6.14,4.945,10.58), (8.95,6.14,10.045,6.44), (10.315,7.88,18.28,8.18), (4.64,10.28,5.845,10.58)])
R(c_3to7_deco_v2, Metal1_pin, [(0.035,0.805,17.03,1.105), (17.03,0.805,18.28,1.105), (0.04,3.205,17.03,3.505), (8.95,3.74,10.04,4.04), (6.89,5.015,7.09,5.435), (8.95,6.14,10.045,6.44)])
R(c_3to7_deco_v2, Metal2, [(2.115,0.575,2.315,1.665), (4,0.575,4.2,1.665), (6.42,0.575,6.62,1.665), (8.12,0.575,8.32,1.665), (10.98,0.575,11.18,1.665), (12.32,0.575,12.52,1.665), (16.48,0.575,16.68,1.665), (7.34,2.075,7.54,3.74), (11.34,2.075,11.54,3.44), (10.4,3.24,10.6,4.595), (10.4,3.24,11.54,3.44), (5.765,3.55,5.965,4.6), (5.765,3.55,7.535,3.75), (6.305,8.965,6.505,10.895), (7.805,8.965,8.005,10.895), (9.295,8.965,9.495,10.895)])
R(c_3to7_deco_v2, pSD, [(0.035,0.805,17.03,1.105), (17.03,0.805,18.28,1.105), (8.95,3.74,10.04,4.04)])
R(c_3to7_deco_v2, Metal3, [(0.505,1.885,0.705,6.85), (16.885,2.085,17.085,6.855), (13.435,5.015,13.635,6.85), (6.89,5.23,7.09,6.855), (0.125,6.65,16.375,6.85), (10.265,6.65,10.465,8.735), (16.14,6.65,17.085,6.85), (9.76,8.54,10.465,8.74)])
R(c_3to7_deco_v2, NWell, [(0.04,3.205,17.03,3.505), (8.95,6.14,10.045,6.44)])
R(c_3to7_deco_v2, Metal4, [(15.405,1.88,15.605,7.265), (1.435,1.885,1.635,7.26), (3.52,2.075,5.18,2.275), (3.52,2.075,3.72,7.26), (11.945,2.08,12.145,7.27), (11.485,4.68,11.685,7.26), (8.75,5.02,8.95,7.26), (0.125,7.06,16.375,7.26), (8.27,7.06,8.47,8.74)])
R(c_3to7_deco_v2, Metal5, [(14.395,1.75,14.595,7.675), (3.03,1.795,3.23,7.67), (5.45,1.805,5.65,3.505), (2.52,1.885,2.72,7.67), (8.59,1.885,8.79,4.235), (13.895,2.08,14.095,7.675), (9.535,2.09,9.735,7.67), (4.02,3.29,5.65,3.505), (4.02,3.29,4.22,7.67), (8.59,4.035,9.31,4.235), (9.11,4.035,9.31,7.68), (0.125,7.47,16.375,7.67), (6.78,7.47,6.98,8.71)])
c_3to7_deco_v2.add(gdstk.Reference(inv, (5.605,7.625)))
c_3to7_deco_v2.add(gdstk.Reference(inv, (7.095,7.625)))
c_3to7_deco_v2.add(gdstk.Reference(inv, (8.585,7.625)))
c_3to7_deco_v2.add(gdstk.Reference(and_custom, (10.68,3.485), rotation=pi, x_reflection=True))
c_3to7_deco_v2.add(gdstk.Reference(or_custom, (13.76,3.46), rotation=pi, x_reflection=True))
c_3to7_deco_v2.add(gdstk.Reference(via_stack_3, (6.88,8.61)))
c_3to7_deco_v2.add(gdstk.Reference(via_stack_3, (6.88,7.57)))
c_3to7_deco_v2.add(gdstk.Reference(via_stack_4, (8.365,8.64)))
c_3to7_deco_v2.add(gdstk.Reference(via_stack_4, (8.365,7.165)))
c_3to7_deco_v2.add(gdstk.Reference(via_stack_6, (9.855,8.64)))
c_3to7_deco_v2.add(gdstk.Reference(via_stack_6, (10.36,6.75)))
c_3to7_deco_v2.add(gdstk.Reference(nand_x3_custom, (17.85,-2.27), rotation=pi, x_reflection=True))
c_3to7_deco_v2.add(gdstk.Reference(nand_custom, (10.995,-0.895)))
c_3to7_deco_v2.add(gdstk.Reference(nand_custom, (12.47,-0.895), rotation=pi, x_reflection=True))
c_3to7_deco_v2.add(gdstk.Reference(inv, (9.49,0.55), rotation=pi, x_reflection=True))
c_3to7_deco_v2.add(gdstk.Reference(nor_custom, (7.715,0.525), rotation=pi, x_reflection=True))
c_3to7_deco_v2.add(gdstk.Reference(nor_custom, (5.305,0.525), rotation=pi, x_reflection=True))
c_3to7_deco_v2.add(gdstk.Reference(nor_x3_custom, (-0.95,-0.06)))
c_3to7_deco_v2.add(gdstk.Reference(via_stack_3, (2.62,1.985)))
c_3to7_deco_v2.add(gdstk.Reference(via_stack_3, (2.62,7.57)))
c_3to7_deco_v2.add(gdstk.Reference(via_stack_4, (1.57,1.985)))
c_3to7_deco_v2.add(gdstk.Reference(via_stack_4, (1.515,7.16)))
c_3to7_deco_v2.add(gdstk.Reference(via_stack_6, (0.57,1.985)))
c_3to7_deco_v2.add(gdstk.Reference(via_stack_6, (0.6,6.75)))
c_3to7_deco_v2.add(gdstk.Reference(via_stack_3, (3.125,7.575)))
c_3to7_deco_v2.add(gdstk.Reference(via_stack_4, (5.035,2.175)))
c_3to7_deco_v2.add(gdstk.Reference(via_stack_4, (3.615,7.165)))
c_3to7_deco_v2.add(gdstk.Reference(via_stack_3, (5.54,1.9)))
c_3to7_deco_v2.add(gdstk.Reference(via_stack_3, (4.12,7.58)))
c_3to7_deco_v2.add(gdstk.Reference(via_stack_1, (7.445,2.175)))
c_3to7_deco_v2.add(gdstk.Reference(via_stack_1, (5.86,4.5)))
c_3to7_deco_v2.add(gdstk.Reference(via_stack_6, (6.99,6.755)))
c_3to7_deco_v2.add(gdstk.Reference(via_stack_4, (8.895,5.12)))
c_3to7_deco_v2.add(gdstk.Reference(via_stack_4, (8.88,7.16)))
c_3to7_deco_v2.add(gdstk.Reference(via_stack_3, (9.2,7.58)))
c_3to7_deco_v2.add(gdstk.Reference(via_stack_3, (9.705,7.575)))
c_3to7_deco_v2.add(gdstk.Reference(via_stack, (11.47,2.175)))
c_3to7_deco_v2.add(gdstk.Reference(via_stack, (10.5,4.5)))
c_3to7_deco_v2.add(gdstk.Reference(via_stack_4, (11.585,4.78)))
c_3to7_deco_v2.add(gdstk.Reference(via_stack_4, (11.545,7.16)))
c_3to7_deco_v2.add(gdstk.Reference(via_stack_6, (13.535,5.11)))
c_3to7_deco_v2.add(gdstk.Reference(via_stack_6, (13.49,6.755)))
c_3to7_deco_v2.add(gdstk.Reference(via_stack_3, (13.95,7.575)))
c_3to7_deco_v2.add(gdstk.Reference(via_stack_3, (14.455,1.855)))
c_3to7_deco_v2.add(gdstk.Reference(via_stack_3, (13.955,2.18)))
c_3to7_deco_v2.add(gdstk.Reference(via_stack_3, (14.5,7.575)))
c_3to7_deco_v2.add(gdstk.Reference(via_stack_4, (12,2.185)))
c_3to7_deco_v2.add(gdstk.Reference(via_stack_4, (12.09,7.17)))
c_3to7_deco_v2.add(gdstk.Reference(via_stack_4, (15.5,1.98)))
c_3to7_deco_v2.add(gdstk.Reference(via_stack_4, (15.505,7.165)))
c_3to7_deco_v2.add(gdstk.Reference(via_stack_6, (16.975,2.185)))
c_3to7_deco_v2.add(gdstk.Reference(via_stack_6, (16.94,6.76)))
c_3to7_deco_v2.add(gdstk.Reference(via_stack, (2.21,1.565)))
c_3to7_deco_v2.add(gdstk.Reference(via_stack, (4.105,1.565)))
c_3to7_deco_v2.add(gdstk.Reference(via_stack, (6.515,1.565)))
c_3to7_deco_v2.add(gdstk.Reference(via_stack, (8.22,1.565)))
c_3to7_deco_v2.add(gdstk.Reference(via_stack, (11.06,1.565)))
c_3to7_deco_v2.add(gdstk.Reference(via_stack, (16.57,1.565)))
c_3to7_deco_v2.add(gdstk.Reference(via_stack, (12.405,1.565)))
c_3to7_deco_v2.add(gdstk.Reference(via_stack, (7.86,9.06)))
c_3to7_deco_v2.add(gdstk.Reference(via_stack, (6.365,9.075)))
c_3to7_deco_v2.add(gdstk.Reference(via_stack, (9.35,9.065)))
c_3to7_deco_v2.add(gdstk.Reference(via_stack_3, (8.73,1.995)))
c_3to7_deco_v2.add(gdstk.Reference(via_stack_3, (3.125,1.9)))
c_3to7_deco_v2.add(gdstk.Reference(via_stack_3, (9.61,2.185)))
c_3to7_deco_v2.add(gdstk.Reference(via_stack_6, (6.945,5.345)))
c_3to7_deco_v2.add(gdstk.Label('VDD', (5.515,10.325), layer=8, texttype=25))
c_3to7_deco_v2.add(gdstk.Label('VSS', (5.995,7.995), layer=8, texttype=25))
c_3to7_deco_v2.add(gdstk.Label('S[2]', (6.375,9.015), layer=8, texttype=25))
c_3to7_deco_v2.add(gdstk.Label('S[1]', (7.87,9.03), layer=8, texttype=25))
c_3to7_deco_v2.add(gdstk.Label('S[0]', (9.35,9.045), layer=8, texttype=25))
c_3to7_deco_v2.add(gdstk.Label('ST[1]', (2.13,1.565), layer=8, texttype=25))
c_3to7_deco_v2.add(gdstk.Label('ST[2]', (4.025,1.525), layer=8, texttype=25))
c_3to7_deco_v2.add(gdstk.Label('ST[3]', (6.475,1.55), layer=8, texttype=25))
c_3to7_deco_v2.add(gdstk.Label('ST[4]', (8.14,1.54), layer=8, texttype=25))
c_3to7_deco_v2.add(gdstk.Label('ST[5]', (10.98,1.52), layer=8, texttype=25))
c_3to7_deco_v2.add(gdstk.Label('ST[6]', (12.355,1.54), layer=8, texttype=25))
c_3to7_deco_v2.add(gdstk.Label('ST[7]', (16.54,1.54), layer=8, texttype=25))

lib.write_gds('3to7_deco_v2.gds')
